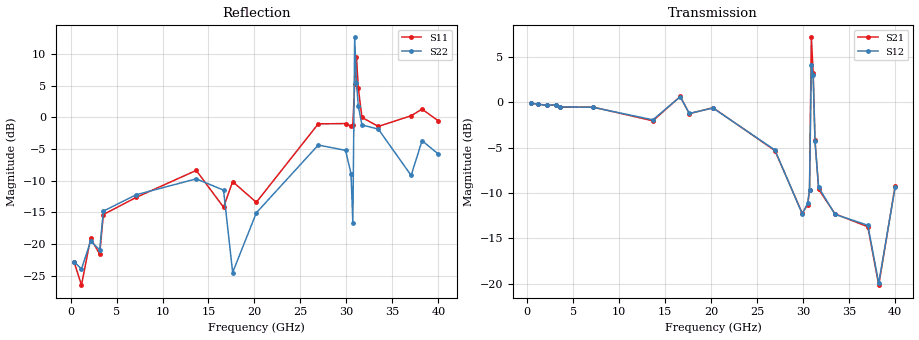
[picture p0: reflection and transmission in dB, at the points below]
! Network Analyzer HP8722ES.07.66: Jul 25, 2000 Serial No. US39175408
! 27 Oct 2004  11:26:08
! Frequency  S11  S21  S12  S22
# HZ  S  DB R  50
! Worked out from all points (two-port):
!   201 points, 400 MHz to 40 GHz, reference 50 ohm
!   highest |S21| = 7.15 dB at 30.89 GHz (marker M1); lowest = -20.1 dB at 38.22 GHz (marker M2)
!   |S21| within 3 dB of the highest: 30.86 GHz to 31.04 GHz (188.3 MHz wide, 0.608 % of centre)
!   lowest |S11| = -26.5 dB at 1.192 GHz (marker M3), VSWR 1.10, Z = 49.8 - j4.75 ohm
!   |S11| at or under -10 dB: start of sweep to 13.21 GHz; 16.11 GHz to 21.35 GHz (5.245 GHz wide, 28 % of centre)
!   |S22| runs from -25.8 to 12.6 dB; largest |S21 - S12| = 1
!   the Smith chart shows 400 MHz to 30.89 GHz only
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4e8  -22.86 -95.2  -0.12 1.5  -0.10 2.0  -22.79 -93.7
1.192e9  -26.46 -89.5  -0.20 -2.6  -0.22 -3.0  -23.93 -95.4
2.182e9  -19.07 -84.8  -0.35 -5.2  -0.34 -4.7  -19.55 -93.0
3.172e9  -21.56 -96.6  -0.28 -11.0  -0.26 -11.0  -20.89 -95.8
3.568e9  -15.33 -88.3  -0.54 -7.5  -0.50 -7.8  -14.79 -95.1
7.132e9  -12.63 -99.8  -0.52 -19.6  -0.55 -20.1  -12.21 -116.4
1.3666e10  -8.37 -74.7  -2.04 -32.4  -1.93 -32.4  -9.70 -124.4
1.6636e10  -14.17 -90.7  0.64 -47.3  0.61 -47.3  -11.48 139.6
1.7626e10  -10.14 -55.5  -1.25 -50.0  -1.23 -50.1  -24.47 103.4
2.02e10  -13.40 -2.5  -0.60 -59.1  -0.63 -59.2  -15.06 51.2
2.6932e10  -1.03 16.2  -5.32 -93.1  -5.26 -93.7  -4.37 -11.1
2.9902e10  -0.98 -4.2  -12.22 -99.6  -12.28 -98.7  -5.21 -51.5
3.0496e10  -1.41 -3.2  -11.27 -91.9  -11.14 -90.4  -8.88 -48.2
3.0694e10  -1.15 -5.9  -9.65 -100.2  -9.62 -99.2  -16.68 -54.4
3.0892e10  5.23 -11.0  7.15 59.6  4.11 36.5  12.61 -43.2
3.109e10  9.47 1.9  3.27 -44.3  3.03 -43.7  5.48 -93.9
3.1288e10  4.58 -20.7  -4.16 -41.1  -4.29 -41.8  1.76 -53.9
3.1684e10  -0.02 -25.2  -9.58 -61.5  -9.37 -61.5  -1.20 -44.2
3.3466e10  -1.43 -23.7  -12.29 -67.7  -12.35 -67.5  -1.86 -52.7
3.703e10  0.25 -24.2  -13.71 -65.9  -13.54 -65.4  -9.16 -36.7
3.8218e10  1.30 -30.9  -20.14 -47.7  -19.93 -45.6  -3.68 -55.2
4e10  -0.57 -43.9  -9.24 -25.1  -9.35 -24.7  -5.80 -81.8
